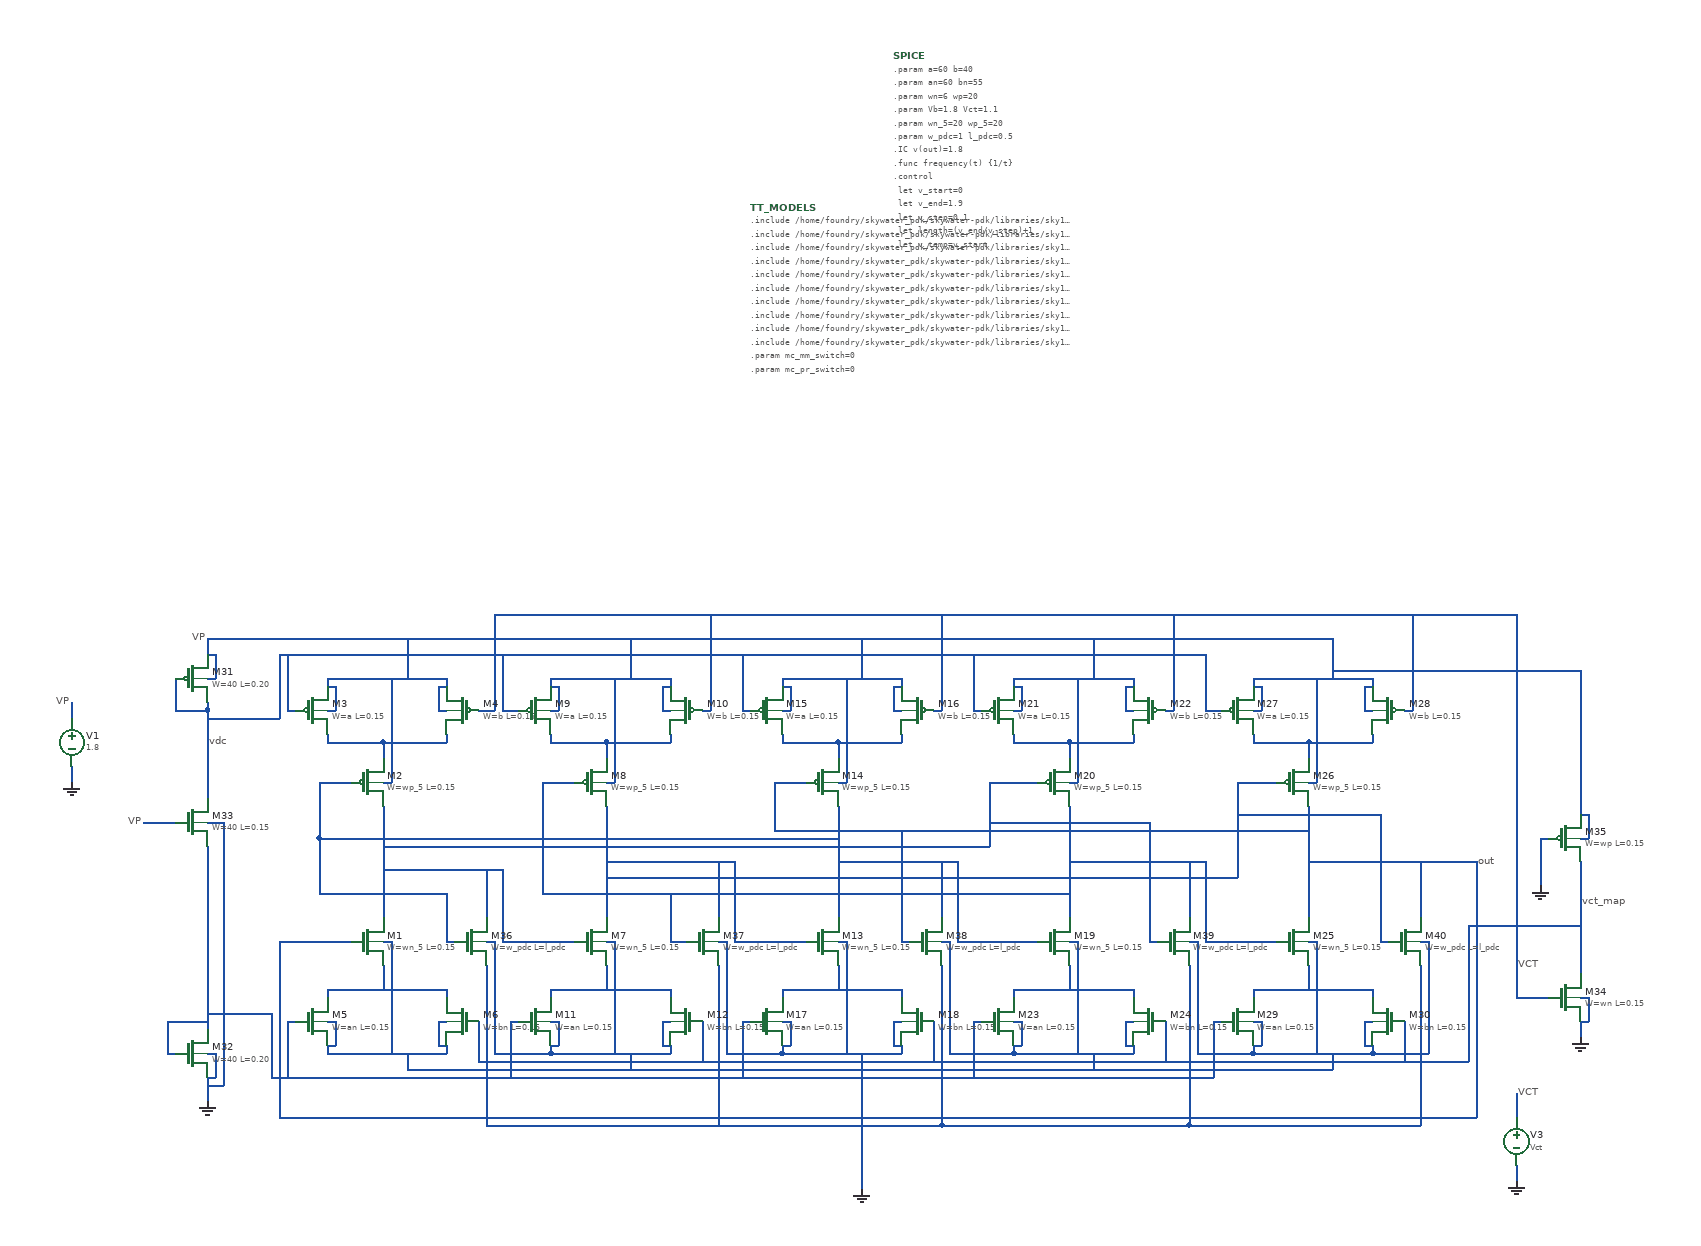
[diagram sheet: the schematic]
v {xschem version=3.0.0 file_version=1.2 }
G {}
K {}
V {}
S {}
E {}
N 50 -260 50 -120 { lab=#net1}
N 50 -290 60 -290 { lab=VP}
N 60 -320 60 -290 { lab=VP}
N 50 -90 60 -90 { lab=GND}
N 60 -90 60 -60 { lab=GND}
N 50 -340 50 -320 { lab=#net2}
N -20 -350 -20 -340 { lab=#net2}
N -20 -340 50 -340 { lab=#net2}
N 130 -350 130 -340 { lab=#net2}
N 50 -340 130 -340 { lab=#net2}
N -20 -380 -10 -380 { lab=VP}
N -10 -410 -10 -380 { lab=VP}
N -20 -410 -10 -410 { lab=VP}
N 120 -380 130 -380 { lab=VP}
N 120 -410 120 -380 { lab=VP}
N 120 -410 130 -410 { lab=VP}
N -20 -420 -20 -410 { lab=VP}
N -20 -420 130 -420 { lab=VP}
N 130 -420 130 -410 { lab=VP}
N -20 -30 -20 -20 { lab=#net3}
N -20 -30 130 -30 { lab=#net3}
N 130 -30 130 -20 { lab=#net3}
N -20 10 -10 10 { lab=GND}
N -10 10 -10 40 { lab=GND}
N -20 40 -10 40 { lab=GND}
N 120 10 130 10 { lab=GND}
N 120 10 120 40 { lab=GND}
N 120 40 130 40 { lab=GND}
N -20 40 -20 50 { lab=GND}
N -20 50 130 50 { lab=GND}
N 130 40 130 50 { lab=GND}
N 50 -60 50 -30 { lab=#net3}
N 330 -260 330 -120 { lab=#net4}
N 330 -290 340 -290 { lab=VP}
N 340 -320 340 -290 { lab=VP}
N 330 -90 340 -90 { lab=GND}
N 340 -90 340 -60 { lab=GND}
N 330 -340 330 -320 { lab=#net5}
N 260 -350 260 -340 { lab=#net5}
N 260 -340 330 -340 { lab=#net5}
N 410 -350 410 -340 { lab=#net5}
N 330 -340 410 -340 { lab=#net5}
N 260 -380 270 -380 { lab=VP}
N 270 -410 270 -380 { lab=VP}
N 260 -410 270 -410 { lab=VP}
N 400 -380 410 -380 { lab=VP}
N 400 -410 400 -380 { lab=VP}
N 400 -410 410 -410 { lab=VP}
N 260 -420 260 -410 { lab=VP}
N 260 -420 410 -420 { lab=VP}
N 410 -420 410 -410 { lab=VP}
N 260 -30 260 -20 { lab=#net6}
N 260 -30 410 -30 { lab=#net6}
N 410 -30 410 -20 { lab=#net6}
N 260 10 270 10 { lab=GND}
N 270 10 270 40 { lab=GND}
N 260 40 270 40 { lab=GND}
N 400 10 410 10 { lab=GND}
N 400 10 400 40 { lab=GND}
N 400 40 410 40 { lab=GND}
N 260 40 260 50 { lab=GND}
N 260 50 410 50 { lab=GND}
N 410 40 410 50 { lab=GND}
N 330 -60 330 -30 { lab=#net6}
N 620 -260 620 -120 { lab=#net7}
N 620 -290 630 -290 { lab=VP}
N 630 -320 630 -290 { lab=VP}
N 620 -90 630 -90 { lab=GND}
N 630 -90 630 -60 { lab=GND}
N 620 -340 620 -320 { lab=#net8}
N 550 -350 550 -340 { lab=#net8}
N 550 -340 620 -340 { lab=#net8}
N 700 -350 700 -340 { lab=#net8}
N 620 -340 700 -340 { lab=#net8}
N 550 -380 560 -380 { lab=VP}
N 560 -410 560 -380 { lab=VP}
N 550 -410 560 -410 { lab=VP}
N 690 -380 700 -380 { lab=VP}
N 690 -410 690 -380 { lab=VP}
N 690 -410 700 -410 { lab=VP}
N 550 -420 550 -410 { lab=VP}
N 550 -420 700 -420 { lab=VP}
N 700 -420 700 -410 { lab=VP}
N 550 -30 550 -20 { lab=#net9}
N 550 -30 700 -30 { lab=#net9}
N 700 -30 700 -20 { lab=#net9}
N 550 10 560 10 { lab=GND}
N 560 10 560 40 { lab=GND}
N 550 40 560 40 { lab=GND}
N 690 10 700 10 { lab=GND}
N 690 10 690 40 { lab=GND}
N 690 40 700 40 { lab=GND}
N 550 40 550 50 { lab=GND}
N 550 50 700 50 { lab=GND}
N 700 40 700 50 { lab=GND}
N 620 -60 620 -30 { lab=#net9}
N 910 -260 910 -120 { lab=#net10}
N 910 -290 920 -290 { lab=VP}
N 920 -320 920 -290 { lab=VP}
N 910 -90 920 -90 { lab=GND}
N 920 -90 920 -60 { lab=GND}
N 910 -340 910 -320 { lab=#net11}
N 840 -350 840 -340 { lab=#net11}
N 840 -340 910 -340 { lab=#net11}
N 990 -350 990 -340 { lab=#net11}
N 910 -340 990 -340 { lab=#net11}
N 840 -380 850 -380 { lab=VP}
N 850 -410 850 -380 { lab=VP}
N 840 -410 850 -410 { lab=VP}
N 980 -380 990 -380 { lab=VP}
N 980 -410 980 -380 { lab=VP}
N 980 -410 990 -410 { lab=VP}
N 840 -420 840 -410 { lab=VP}
N 840 -420 990 -420 { lab=VP}
N 990 -420 990 -410 { lab=VP}
N 840 -30 840 -20 { lab=#net12}
N 840 -30 990 -30 { lab=#net12}
N 990 -30 990 -20 { lab=#net12}
N 840 10 850 10 { lab=GND}
N 850 10 850 40 { lab=GND}
N 840 40 850 40 { lab=GND}
N 980 10 990 10 { lab=GND}
N 980 10 980 40 { lab=GND}
N 980 40 990 40 { lab=GND}
N 840 40 840 50 { lab=GND}
N 840 50 990 50 { lab=GND}
N 990 40 990 50 { lab=GND}
N 910 -60 910 -30 { lab=#net12}
N 1210 -260 1210 -120 { lab=out}
N 1210 -290 1220 -290 { lab=VP}
N 1220 -320 1220 -290 { lab=VP}
N 1210 -90 1220 -90 { lab=GND}
N 1220 -90 1220 -60 { lab=GND}
N 1210 -340 1210 -320 { lab=#net13}
N 1140 -350 1140 -340 { lab=#net13}
N 1140 -340 1210 -340 { lab=#net13}
N 1290 -350 1290 -340 { lab=#net13}
N 1210 -340 1290 -340 { lab=#net13}
N 1140 -380 1150 -380 { lab=VP}
N 1150 -410 1150 -380 { lab=VP}
N 1140 -410 1150 -410 { lab=VP}
N 1280 -380 1290 -380 { lab=VP}
N 1280 -410 1280 -380 { lab=VP}
N 1280 -410 1290 -410 { lab=VP}
N 1140 -420 1140 -410 { lab=VP}
N 1140 -420 1290 -420 { lab=VP}
N 1290 -420 1290 -410 { lab=VP}
N 1140 -30 1140 -20 { lab=#net14}
N 1140 -30 1290 -30 { lab=#net14}
N 1290 -30 1290 -20 { lab=#net14}
N 1140 10 1150 10 { lab=GND}
N 1150 10 1150 40 { lab=GND}
N 1140 40 1150 40 { lab=GND}
N 1280 10 1290 10 { lab=GND}
N 1280 10 1280 40 { lab=GND}
N 1280 40 1290 40 { lab=GND}
N 1140 40 1140 50 { lab=GND}
N 1140 50 1290 50 { lab=GND}
N 1290 40 1290 50 { lab=GND}
N 1210 -60 1210 -30 { lab=#net14}
N 60 -420 60 -320 { lab=VP}
N 340 -420 340 -320 { lab=VP}
N 630 -420 630 -320 { lab=VP}
N 920 -420 920 -320 { lab=VP}
N 1220 -420 1220 -320 { lab=VP}
N 60 -60 60 50 { lab=GND}
N 340 -60 340 50 { lab=GND}
N 630 -60 630 50 { lab=GND}
N 920 -60 920 50 { lab=GND}
N 1220 -60 1220 50 { lab=GND}
N 200 -90 290 -90 { lab=#net1}
N 200 -180 200 -90 { lab=#net1}
N 50 -180 200 -180 { lab=#net1}
N 490 -90 580 -90 { lab=#net4}
N 490 -190 490 -90 { lab=#net4}
N 330 -190 490 -190 { lab=#net4}
N 770 -90 870 -90 { lab=#net7}
N 770 -190 770 -90 { lab=#net7}
N 620 -190 770 -190 { lab=#net7}
N 910 -190 1070 -190 { lab=#net10}
N 1080 -190 1080 -90 { lab=#net10}
N -80 -90 -80 130 { lab=out}
N 1420 -190 1420 130 { lab=out}
N -340 -310 -340 -290 { lab=GND}
N -170 -470 1240 -470 { lab=VP}
N 1240 -460 1240 -420 { lab=VP}
N 80 -460 80 -420 { lab=VP}
N 360 -460 360 -420 { lab=VP}
N 650 -460 650 -420 { lab=VP}
N 940 -460 940 -420 { lab=VP}
N 80 50 80 70 { lab=GND}
N 80 70 1240 70 { lab=GND}
N 1240 50 1240 70 { lab=GND}
N 360 50 360 70 { lab=GND}
N 650 50 650 70 { lab=GND}
N 940 50 940 70 { lab=GND}
N 650 70 650 90 { lab=GND}
N 810 -290 870 -290 { lab=#net1}
N 810 -290 810 -210 { lab=#net1}
N 50 -210 810 -210 { lab=#net1}
N 1120 -290 1170 -290 { lab=#net4}
N 1120 -290 1120 -170 { lab=#net4}
N 330 -170 1120 -170 { lab=#net4}
N -30 -290 10 -290 { lab=#net7}
N -30 -290 -30 -220 { lab=#net7}
N -30 -220 620 -220 { lab=#net7}
N 250 -290 290 -290 { lab=#net10}
N 250 -290 250 -150 { lab=#net10}
N 250 -150 910 -150 { lab=#net10}
N 540 -290 580 -290 { lab=out}
N 540 -290 540 -230 { lab=out}
N 540 -230 1210 -230 { lab=out}
N -80 -90 10 -90 { lab=out}
N -210 -420 -210 -380 { lab=vdc}
N -210 -380 -170 -380 { lab=vdc}
N -170 -390 -170 -380 { lab=vdc}
N -170 -420 -160 -420 { lab=VP}
N -160 -450 -160 -420 { lab=VP}
N -170 -450 -160 -450 { lab=VP}
N 80 -470 80 -460 { lab=VP}
N 360 -470 360 -460 { lab=VP}
N 650 -470 650 -460 { lab=VP}
N 940 -470 940 -460 { lab=VP}
N 1240 -470 1240 -460 { lab=VP}
N -170 -470 -170 -450 { lab=VP}
N -170 -210 -170 20 { lab=#net15}
N -170 -380 -170 -270 { lab=vdc}
N -220 50 -210 50 { lab=#net15}
N -220 10 -220 50 { lab=#net15}
N -220 10 -170 10 { lab=#net15}
N -170 0 -90 0 { lab=#net15}
N -90 0 -90 80 { lab=#net15}
N -90 80 1090 80 { lab=#net15}
N 1090 10 1090 80 { lab=#net15}
N 1090 10 1100 10 { lab=#net15}
N 790 10 800 10 { lab=#net15}
N 790 10 790 80 { lab=#net15}
N 500 10 510 10 { lab=#net15}
N 500 10 500 80 { lab=#net15}
N 210 10 220 10 { lab=#net15}
N 210 10 210 80 { lab=#net15}
N -70 10 -60 10 { lab=#net15}
N -70 10 -70 80 { lab=#net15}
N -170 50 -160 50 { lab=GND}
N -160 50 -160 80 { lab=GND}
N -170 80 -160 80 { lab=GND}
N -170 80 -170 110 { lab=GND}
N -170 -370 -80 -370 { lab=vdc}
N -80 -450 -80 -370 { lab=vdc}
N -80 -450 1080 -450 { lab=vdc}
N 1080 -450 1080 -380 { lab=vdc}
N 1080 -380 1100 -380 { lab=vdc}
N 790 -380 800 -380 { lab=vdc}
N 790 -450 790 -380 { lab=vdc}
N 1470 190 1470 210 { lab=GND}
N 1470 -20 1510 -20 { lab=vct}
N 1550 -20 1560 -20 { lab=GND}
N 1560 -20 1560 10 { lab=GND}
N 1550 10 1560 10 { lab=GND}
N 1550 10 1550 30 { lab=GND}
N 1550 -220 1560 -220 { lab=VP}
N 1560 -250 1560 -220 { lab=VP}
N 1550 -250 1560 -250 { lab=VP}
N 1550 -430 1550 -250 { lab=VP}
N 1240 -430 1550 -430 { lab=VP}
N 1550 -190 1550 -50 { lab=vct_map}
N 1470 -500 1470 -20 { lab=vct}
N 190 -500 1470 -500 { lab=vct}
N 190 -500 190 -380 { lab=vct}
N 170 -380 190 -380 { lab=vct}
N -70 -380 -60 -380 { lab=vdc}
N -70 -450 -70 -380 { lab=vdc}
N 200 -380 220 -380 { lab=vdc}
N 200 -450 200 -380 { lab=vdc}
N 500 -380 510 -380 { lab=vdc}
N 500 -450 500 -380 { lab=vdc}
N 450 -380 460 -380 { lab=vct}
N 460 -500 460 -380 { lab=vct}
N 740 -380 750 -380 { lab=vct}
N 750 -500 750 -380 { lab=vct}
N 1030 -380 1040 -380 { lab=vct}
N 1040 -500 1040 -380 { lab=vct}
N 1500 -220 1510 -220 { lab=GND}
N 1500 -220 1500 -180 { lab=GND}
N 1450 -110 1550 -110 { lab=vct_map}
N 1410 -110 1450 -110 { lab=vct_map}
N 1410 -110 1410 60 { lab=vct_map}
N 170 60 1410 60 { lab=vct_map}
N 170 10 170 60 { lab=vct_map}
N 450 10 450 60 { lab=vct_map}
N 740 10 740 60 { lab=vct_map}
N 1030 10 1030 60 { lab=vct_map}
N 1330 10 1330 60 { lab=vct_map}
N 1330 -380 1340 -380 { lab=vct}
N 1340 -500 1340 -380 { lab=vct}
N 1210 -190 1360 -190 { lab=out}
N -80 130 1360 130 { lab=out}
N 1500 -180 1500 -160 { lab=GND}
N -170 -240 -150 -240 { lab=GND}
N -150 -240 -150 90 { lab=GND}
N -170 90 -150 90 { lab=GND}
N -250 -240 -210 -240 { lab=VP}
N 180 -60 180 140 { lab=GND}
N 470 -60 470 140 { lab=GND}
N 750 -60 750 140 { lab=GND}
N 1060 -60 1060 140 { lab=GND}
N 1350 -60 1350 140 { lab=GND}
N 650 90 650 220 { lab=GND}
N 180 -180 180 -120 { lab=#net1}
N 470 -190 470 -120 { lab=#net4}
N 750 -190 750 -120 { lab=#net7}
N 1060 -190 1060 -120 { lab=#net10}
N 1350 -190 1350 -120 { lab=out}
N 130 -90 140 -90 { lab=#net7}
N 130 -150 130 -90 { lab=#net7}
N -30 -150 130 -150 { lab=#net7}
N -30 -220 -30 -150 { lab=#net7}
N 410 -90 430 -90 { lab=#net10}
N 410 -150 410 -90 { lab=#net10}
N 700 -90 710 -90 { lab=out}
N 700 -230 700 -90 { lab=out}
N 1010 -90 1020 -90 { lab=#net1}
N 1010 -240 1010 -90 { lab=#net1}
N 810 -240 1010 -240 { lab=#net1}
N 1300 -90 1310 -90 { lab=#net4}
N 1300 -250 1300 -90 { lab=#net4}
N 1120 -250 1300 -250 { lab=#net4}
N 180 -90 190 -90 { lab=GND}
N 190 -90 190 50 { lab=GND}
N 190 50 260 50 { lab=GND}
N 470 -90 480 -90 { lab=GND}
N 480 -90 480 50 { lab=GND}
N 480 50 550 50 { lab=GND}
N 750 -90 760 -90 { lab=GND}
N 760 -90 760 50 { lab=GND}
N 760 50 840 50 { lab=GND}
N 1070 50 1140 50 { lab=GND}
N 1070 -190 1080 -190 { lab=#net10}
N 1080 -90 1170 -90 { lab=#net10}
N 1060 -90 1070 -90 { lab=GND}
N 1070 -90 1070 50 { lab=GND}
N 1360 130 1420 130 { lab=out}
N 1360 -190 1420 -190 { lab=out}
N 1350 -90 1360 -90 { lab=GND}
N 1360 -90 1360 50 { lab=GND}
N 1290 50 1360 50 { lab=GND}
N 180 140 650 140 { lab=GND}
N 650 140 750 140 { lab=GND}
N 750 140 1060 140 { lab=GND}
N 1060 140 1350 140 { lab=GND}
N -340 -390 -340 -370 { lab=VP}
N 1470 100 1470 130 { lab=VCT}
C {xschem_sky130/sky130_fd_pr/nfet_01v8.sym} 30 -90 0 0 {name=M1
L=0.15
W=wn_5
nf=4 
mult=1
ad="'int((nf+1)/2) * W/nf * 0.29'" 
pd="'2*int((nf+1)/2) * (W/nf + 0.29)'"
as="'int((nf+2)/2) * W/nf * 0.29'" 
ps="'2*int((nf+2)/2) * (W/nf + 0.29)'"
nrd="'0.29 / W'" nrs="'0.29 / W'"
sa=0 sb=0 sd=0
model=nfet_01v8
spiceprefix=X
}
C {xschem_sky130/sky130_fd_pr/pfet_01v8.sym} 30 -290 0 0 {name=M2
L=0.15
W=wp_5
nf=4
mult=1
ad="'int((nf+1)/2) * W/nf * 0.29'" 
pd="'2*int((nf+1)/2) * (W/nf + 0.29)'"
as="'int((nf+2)/2) * W/nf * 0.29'" 
ps="'2*int((nf+2)/2) * (W/nf + 0.29)'"
nrd="'0.29 / W'" nrs="'0.29 / W'"
sa=0 sb=0 sd=0
model=pfet_01v8
spiceprefix=X
}
C {xschem_sky130/sky130_fd_pr/pfet_01v8.sym} -40 -380 0 0 {name=M3
L=0.15
W=a
nf=12
mult=1
ad="'int((nf+1)/2) * W/nf * 0.29'" 
pd="'2*int((nf+1)/2) * (W/nf + 0.29)'"
as="'int((nf+2)/2) * W/nf * 0.29'" 
ps="'2*int((nf+2)/2) * (W/nf + 0.29)'"
nrd="'0.29 / W'" nrs="'0.29 / W'"
sa=0 sb=0 sd=0
model=pfet_01v8
spiceprefix=X
}
C {xschem_sky130/sky130_fd_pr/pfet_01v8.sym} 150 -380 0 1 {name=M4
L=0.15
W=b
nf=8
mult=1
ad="'int((nf+1)/2) * W/nf * 0.29'" 
pd="'2*int((nf+1)/2) * (W/nf + 0.29)'"
as="'int((nf+2)/2) * W/nf * 0.29'" 
ps="'2*int((nf+2)/2) * (W/nf + 0.29)'"
nrd="'0.29 / W'" nrs="'0.29 / W'"
sa=0 sb=0 sd=0
model=pfet_01v8
spiceprefix=X
}
C {xschem_sky130/sky130_fd_pr/nfet_01v8.sym} -40 10 0 0 {name=M5
L=0.15
W=an
nf=12 
mult=1
ad="'int((nf+1)/2) * W/nf * 0.29'" 
pd="'2*int((nf+1)/2) * (W/nf + 0.29)'"
as="'int((nf+2)/2) * W/nf * 0.29'" 
ps="'2*int((nf+2)/2) * (W/nf + 0.29)'"
nrd="'0.29 / W'" nrs="'0.29 / W'"
sa=0 sb=0 sd=0
model=nfet_01v8
spiceprefix=X
}
C {xschem_sky130/sky130_fd_pr/nfet_01v8.sym} 150 10 0 1 {name=M6
L=0.15
W=bn
nf=11 
mult=1
ad="'int((nf+1)/2) * W/nf * 0.29'" 
pd="'2*int((nf+1)/2) * (W/nf + 0.29)'"
as="'int((nf+2)/2) * W/nf * 0.29'" 
ps="'2*int((nf+2)/2) * (W/nf + 0.29)'"
nrd="'0.29 / W'" nrs="'0.29 / W'"
sa=0 sb=0 sd=0
model=nfet_01v8
spiceprefix=X
}
C {xschem_sky130/sky130_fd_pr/nfet_01v8.sym} 310 -90 0 0 {name=M7
L=0.15
W=wn_5
nf=4 
mult=1
ad="'int((nf+1)/2) * W/nf * 0.29'" 
pd="'2*int((nf+1)/2) * (W/nf + 0.29)'"
as="'int((nf+2)/2) * W/nf * 0.29'" 
ps="'2*int((nf+2)/2) * (W/nf + 0.29)'"
nrd="'0.29 / W'" nrs="'0.29 / W'"
sa=0 sb=0 sd=0
model=nfet_01v8
spiceprefix=X
}
C {xschem_sky130/sky130_fd_pr/pfet_01v8.sym} 310 -290 0 0 {name=M8
L=0.15
W=wp_5
nf=4
mult=1
ad="'int((nf+1)/2) * W/nf * 0.29'" 
pd="'2*int((nf+1)/2) * (W/nf + 0.29)'"
as="'int((nf+2)/2) * W/nf * 0.29'" 
ps="'2*int((nf+2)/2) * (W/nf + 0.29)'"
nrd="'0.29 / W'" nrs="'0.29 / W'"
sa=0 sb=0 sd=0
model=pfet_01v8
spiceprefix=X
}
C {xschem_sky130/sky130_fd_pr/pfet_01v8.sym} 240 -380 0 0 {name=M9
L=0.15
W=a
nf=12
mult=1
ad="'int((nf+1)/2) * W/nf * 0.29'" 
pd="'2*int((nf+1)/2) * (W/nf + 0.29)'"
as="'int((nf+2)/2) * W/nf * 0.29'" 
ps="'2*int((nf+2)/2) * (W/nf + 0.29)'"
nrd="'0.29 / W'" nrs="'0.29 / W'"
sa=0 sb=0 sd=0
model=pfet_01v8
spiceprefix=X
}
C {xschem_sky130/sky130_fd_pr/pfet_01v8.sym} 430 -380 0 1 {name=M10
L=0.15
W=b
nf=8
mult=1
ad="'int((nf+1)/2) * W/nf * 0.29'" 
pd="'2*int((nf+1)/2) * (W/nf + 0.29)'"
as="'int((nf+2)/2) * W/nf * 0.29'" 
ps="'2*int((nf+2)/2) * (W/nf + 0.29)'"
nrd="'0.29 / W'" nrs="'0.29 / W'"
sa=0 sb=0 sd=0
model=pfet_01v8
spiceprefix=X
}
C {xschem_sky130/sky130_fd_pr/nfet_01v8.sym} 240 10 0 0 {name=M11
L=0.15
W=an
nf=12 
mult=1
ad="'int((nf+1)/2) * W/nf * 0.29'" 
pd="'2*int((nf+1)/2) * (W/nf + 0.29)'"
as="'int((nf+2)/2) * W/nf * 0.29'" 
ps="'2*int((nf+2)/2) * (W/nf + 0.29)'"
nrd="'0.29 / W'" nrs="'0.29 / W'"
sa=0 sb=0 sd=0
model=nfet_01v8
spiceprefix=X
}
C {xschem_sky130/sky130_fd_pr/nfet_01v8.sym} 430 10 0 1 {name=M12
L=0.15
W=bn
nf=11 
mult=1
ad="'int((nf+1)/2) * W/nf * 0.29'" 
pd="'2*int((nf+1)/2) * (W/nf + 0.29)'"
as="'int((nf+2)/2) * W/nf * 0.29'" 
ps="'2*int((nf+2)/2) * (W/nf + 0.29)'"
nrd="'0.29 / W'" nrs="'0.29 / W'"
sa=0 sb=0 sd=0
model=nfet_01v8
spiceprefix=X
}
C {xschem_sky130/sky130_fd_pr/nfet_01v8.sym} 600 -90 0 0 {name=M13
L=0.15
W=wn_5
nf=4 
mult=1
ad="'int((nf+1)/2) * W/nf * 0.29'" 
pd="'2*int((nf+1)/2) * (W/nf + 0.29)'"
as="'int((nf+2)/2) * W/nf * 0.29'" 
ps="'2*int((nf+2)/2) * (W/nf + 0.29)'"
nrd="'0.29 / W'" nrs="'0.29 / W'"
sa=0 sb=0 sd=0
model=nfet_01v8
spiceprefix=X
}
C {xschem_sky130/sky130_fd_pr/pfet_01v8.sym} 600 -290 0 0 {name=M14
L=0.15
W=wp_5
nf=4
mult=1
ad="'int((nf+1)/2) * W/nf * 0.29'" 
pd="'2*int((nf+1)/2) * (W/nf + 0.29)'"
as="'int((nf+2)/2) * W/nf * 0.29'" 
ps="'2*int((nf+2)/2) * (W/nf + 0.29)'"
nrd="'0.29 / W'" nrs="'0.29 / W'"
sa=0 sb=0 sd=0
model=pfet_01v8
spiceprefix=X
}
C {xschem_sky130/sky130_fd_pr/pfet_01v8.sym} 530 -380 0 0 {name=M15
L=0.15
W=a
nf=12
mult=1
ad="'int((nf+1)/2) * W/nf * 0.29'" 
pd="'2*int((nf+1)/2) * (W/nf + 0.29)'"
as="'int((nf+2)/2) * W/nf * 0.29'" 
ps="'2*int((nf+2)/2) * (W/nf + 0.29)'"
nrd="'0.29 / W'" nrs="'0.29 / W'"
sa=0 sb=0 sd=0
model=pfet_01v8
spiceprefix=X
}
C {xschem_sky130/sky130_fd_pr/pfet_01v8.sym} 720 -380 0 1 {name=M16
L=0.15
W=b
nf=8
mult=1
ad="'int((nf+1)/2) * W/nf * 0.29'" 
pd="'2*int((nf+1)/2) * (W/nf + 0.29)'"
as="'int((nf+2)/2) * W/nf * 0.29'" 
ps="'2*int((nf+2)/2) * (W/nf + 0.29)'"
nrd="'0.29 / W'" nrs="'0.29 / W'"
sa=0 sb=0 sd=0
model=pfet_01v8
spiceprefix=X
}
C {xschem_sky130/sky130_fd_pr/nfet_01v8.sym} 530 10 0 0 {name=M17
L=0.15
W=an
nf=12 
mult=1
ad="'int((nf+1)/2) * W/nf * 0.29'" 
pd="'2*int((nf+1)/2) * (W/nf + 0.29)'"
as="'int((nf+2)/2) * W/nf * 0.29'" 
ps="'2*int((nf+2)/2) * (W/nf + 0.29)'"
nrd="'0.29 / W'" nrs="'0.29 / W'"
sa=0 sb=0 sd=0
model=nfet_01v8
spiceprefix=X
}
C {xschem_sky130/sky130_fd_pr/nfet_01v8.sym} 720 10 0 1 {name=M18
L=0.15
W=bn
nf=11 
mult=1
ad="'int((nf+1)/2) * W/nf * 0.29'" 
pd="'2*int((nf+1)/2) * (W/nf + 0.29)'"
as="'int((nf+2)/2) * W/nf * 0.29'" 
ps="'2*int((nf+2)/2) * (W/nf + 0.29)'"
nrd="'0.29 / W'" nrs="'0.29 / W'"
sa=0 sb=0 sd=0
model=nfet_01v8
spiceprefix=X
}
C {xschem_sky130/sky130_fd_pr/nfet_01v8.sym} 890 -90 0 0 {name=M19
L=0.15
W=wn_5
nf=4 
mult=1
ad="'int((nf+1)/2) * W/nf * 0.29'" 
pd="'2*int((nf+1)/2) * (W/nf + 0.29)'"
as="'int((nf+2)/2) * W/nf * 0.29'" 
ps="'2*int((nf+2)/2) * (W/nf + 0.29)'"
nrd="'0.29 / W'" nrs="'0.29 / W'"
sa=0 sb=0 sd=0
model=nfet_01v8
spiceprefix=X
}
C {xschem_sky130/sky130_fd_pr/pfet_01v8.sym} 890 -290 0 0 {name=M20
L=0.15
W=wp_5
nf=4
mult=1
ad="'int((nf+1)/2) * W/nf * 0.29'" 
pd="'2*int((nf+1)/2) * (W/nf + 0.29)'"
as="'int((nf+2)/2) * W/nf * 0.29'" 
ps="'2*int((nf+2)/2) * (W/nf + 0.29)'"
nrd="'0.29 / W'" nrs="'0.29 / W'"
sa=0 sb=0 sd=0
model=pfet_01v8
spiceprefix=X
}
C {xschem_sky130/sky130_fd_pr/pfet_01v8.sym} 820 -380 0 0 {name=M21
L=0.15
W=a
nf=12
mult=1
ad="'int((nf+1)/2) * W/nf * 0.29'" 
pd="'2*int((nf+1)/2) * (W/nf + 0.29)'"
as="'int((nf+2)/2) * W/nf * 0.29'" 
ps="'2*int((nf+2)/2) * (W/nf + 0.29)'"
nrd="'0.29 / W'" nrs="'0.29 / W'"
sa=0 sb=0 sd=0
model=pfet_01v8
spiceprefix=X
}
C {xschem_sky130/sky130_fd_pr/pfet_01v8.sym} 1010 -380 0 1 {name=M22
L=0.15
W=b
nf=8
mult=1
ad="'int((nf+1)/2) * W/nf * 0.29'" 
pd="'2*int((nf+1)/2) * (W/nf + 0.29)'"
as="'int((nf+2)/2) * W/nf * 0.29'" 
ps="'2*int((nf+2)/2) * (W/nf + 0.29)'"
nrd="'0.29 / W'" nrs="'0.29 / W'"
sa=0 sb=0 sd=0
model=pfet_01v8
spiceprefix=X
}
C {xschem_sky130/sky130_fd_pr/nfet_01v8.sym} 820 10 0 0 {name=M23
L=0.15
W=an
nf=12 
mult=1
ad="'int((nf+1)/2) * W/nf * 0.29'" 
pd="'2*int((nf+1)/2) * (W/nf + 0.29)'"
as="'int((nf+2)/2) * W/nf * 0.29'" 
ps="'2*int((nf+2)/2) * (W/nf + 0.29)'"
nrd="'0.29 / W'" nrs="'0.29 / W'"
sa=0 sb=0 sd=0
model=nfet_01v8
spiceprefix=X
}
C {xschem_sky130/sky130_fd_pr/nfet_01v8.sym} 1010 10 0 1 {name=M24
L=0.15
W=bn
nf=11 
mult=1
ad="'int((nf+1)/2) * W/nf * 0.29'" 
pd="'2*int((nf+1)/2) * (W/nf + 0.29)'"
as="'int((nf+2)/2) * W/nf * 0.29'" 
ps="'2*int((nf+2)/2) * (W/nf + 0.29)'"
nrd="'0.29 / W'" nrs="'0.29 / W'"
sa=0 sb=0 sd=0
model=nfet_01v8
spiceprefix=X
}
C {xschem_sky130/sky130_fd_pr/nfet_01v8.sym} 1190 -90 0 0 {name=M25
L=0.15
W=wn_5
nf=4 
mult=1
ad="'int((nf+1)/2) * W/nf * 0.29'" 
pd="'2*int((nf+1)/2) * (W/nf + 0.29)'"
as="'int((nf+2)/2) * W/nf * 0.29'" 
ps="'2*int((nf+2)/2) * (W/nf + 0.29)'"
nrd="'0.29 / W'" nrs="'0.29 / W'"
sa=0 sb=0 sd=0
model=nfet_01v8
spiceprefix=X
}
C {xschem_sky130/sky130_fd_pr/pfet_01v8.sym} 1190 -290 0 0 {name=M26
L=0.15
W=wp_5
nf=4
mult=1
ad="'int((nf+1)/2) * W/nf * 0.29'" 
pd="'2*int((nf+1)/2) * (W/nf + 0.29)'"
as="'int((nf+2)/2) * W/nf * 0.29'" 
ps="'2*int((nf+2)/2) * (W/nf + 0.29)'"
nrd="'0.29 / W'" nrs="'0.29 / W'"
sa=0 sb=0 sd=0
model=pfet_01v8
spiceprefix=X
}
C {xschem_sky130/sky130_fd_pr/pfet_01v8.sym} 1120 -380 0 0 {name=M27
L=0.15
W=a
nf=12
mult=1
ad="'int((nf+1)/2) * W/nf * 0.29'" 
pd="'2*int((nf+1)/2) * (W/nf + 0.29)'"
as="'int((nf+2)/2) * W/nf * 0.29'" 
ps="'2*int((nf+2)/2) * (W/nf + 0.29)'"
nrd="'0.29 / W'" nrs="'0.29 / W'"
sa=0 sb=0 sd=0
model=pfet_01v8
spiceprefix=X
}
C {xschem_sky130/sky130_fd_pr/pfet_01v8.sym} 1310 -380 0 1 {name=M28
L=0.15
W=b
nf=8
mult=1
ad="'int((nf+1)/2) * W/nf * 0.29'" 
pd="'2*int((nf+1)/2) * (W/nf + 0.29)'"
as="'int((nf+2)/2) * W/nf * 0.29'" 
ps="'2*int((nf+2)/2) * (W/nf + 0.29)'"
nrd="'0.29 / W'" nrs="'0.29 / W'"
sa=0 sb=0 sd=0
model=pfet_01v8
spiceprefix=X
}
C {xschem_sky130/sky130_fd_pr/nfet_01v8.sym} 1120 10 0 0 {name=M29
L=0.15
W=an
nf=12 
mult=1
ad="'int((nf+1)/2) * W/nf * 0.29'" 
pd="'2*int((nf+1)/2) * (W/nf + 0.29)'"
as="'int((nf+2)/2) * W/nf * 0.29'" 
ps="'2*int((nf+2)/2) * (W/nf + 0.29)'"
nrd="'0.29 / W'" nrs="'0.29 / W'"
sa=0 sb=0 sd=0
model=nfet_01v8
spiceprefix=X
}
C {xschem_sky130/sky130_fd_pr/nfet_01v8.sym} 1310 10 0 1 {name=M30
L=0.15
W=bn
nf=11 
mult=1
ad="'int((nf+1)/2) * W/nf * 0.29'" 
pd="'2*int((nf+1)/2) * (W/nf + 0.29)'"
as="'int((nf+2)/2) * W/nf * 0.29'" 
ps="'2*int((nf+2)/2) * (W/nf + 0.29)'"
nrd="'0.29 / W'" nrs="'0.29 / W'"
sa=0 sb=0 sd=0
model=nfet_01v8
spiceprefix=X
}
C {vsource.sym} -340 -340 0 0 {name=V1 value=1.8}
C {gnd.sym} -340 -290 0 0 {name=l1 lab=GND}
C {xschem_sky130/sky130_fd_pr/pfet_01v8.sym} -190 -420 0 0 {name=M31
L=0.20
W=40
nf=8
mult=1
ad="'int((nf+1)/2) * W/nf * 0.29'" 
pd="'2*int((nf+1)/2) * (W/nf + 0.29)'"
as="'int((nf+2)/2) * W/nf * 0.29'" 
ps="'2*int((nf+2)/2) * (W/nf + 0.29)'"
nrd="'0.29 / W'" nrs="'0.29 / W'"
sa=0 sb=0 sd=0
model=pfet_01v8
spiceprefix=X
}
C {xschem_sky130/sky130_fd_pr/nfet_01v8.sym} -190 50 0 0 {name=M32
L=0.20
W=40
nf=8
mult=1
ad="'int((nf+1)/2) * W/nf * 0.29'" 
pd="'2*int((nf+1)/2) * (W/nf + 0.29)'"
as="'int((nf+2)/2) * W/nf * 0.29'" 
ps="'2*int((nf+2)/2) * (W/nf + 0.29)'"
nrd="'0.29 / W'" nrs="'0.29 / W'"
sa=0 sb=0 sd=0
model=nfet_01v8
spiceprefix=X
}
C {gnd.sym} -170 110 0 0 {name=l4 lab=GND}
C {xschem_sky130/sky130_fd_pr/nfet_01v8.sym} 1530 -20 0 0 {name=M34
L=0.15
W=wn
nf=1 
mult=1
ad="'int((nf+1)/2) * W/nf * 0.29'" 
pd="'2*int((nf+1)/2) * (W/nf + 0.29)'"
as="'int((nf+2)/2) * W/nf * 0.29'" 
ps="'2*int((nf+2)/2) * (W/nf + 0.29)'"
nrd="'0.29 / W'" nrs="'0.29 / W'"
sa=0 sb=0 sd=0
model=nfet_01v8
spiceprefix=X
}
C {vsource.sym} 1470 160 0 0 {name=V3 value=Vct}
C {gnd.sym} 1470 210 0 0 {name=l5 lab=GND}
C {xschem_sky130/sky130_fd_pr/pfet_01v8.sym} 1530 -220 0 0 {name=M35
L=0.15
W=wp
nf=4
mult=1
ad="'int((nf+1)/2) * W/nf * 0.29'" 
pd="'2*int((nf+1)/2) * (W/nf + 0.29)'"
as="'int((nf+2)/2) * W/nf * 0.29'" 
ps="'2*int((nf+2)/2) * (W/nf + 0.29)'"
nrd="'0.29 / W'" nrs="'0.29 / W'"
sa=0 sb=0 sd=0
model=pfet_01v8
spiceprefix=X
}
C {gnd.sym} 1550 30 0 0 {name=l6 lab=GND}
C {code.sym} 510 -1010 0 0 {name=TT_MODELS
only_toplevel=true
format="tcleval( @value )"
value=".include /home/foundry/skywater_pdk/skywater-pdk/libraries/sky130_fd_pr_ngspice/latest/models/corners/tt/nonfet.spice
.include /home/foundry/skywater_pdk/skywater-pdk/libraries/sky130_fd_pr_ngspice/latest/models/all.spice 
.include /home/foundry/skywater_pdk/skywater-pdk/libraries/sky130_fd_pr/latest/cells/pfet_01v8_lvt/sky130_fd_pr__pfet_01v8_lvt__tt.corner.spice
.include /home/foundry/skywater_pdk/skywater-pdk/libraries/sky130_fd_pr/latest/cells/nfet_01v8_lvt/sky130_fd_pr__nfet_01v8_lvt__tt.corner.spice
.include /home/foundry/skywater_pdk/skywater-pdk/libraries/sky130_fd_pr/latest/cells/pfet_01v8_lvt/sky130_fd_pr__pfet_01v8_lvt__mismatch.corner.spice
.include /home/foundry/skywater_pdk/skywater-pdk/libraries/sky130_fd_pr/latest/cells/nfet_01v8_lvt/sky130_fd_pr__nfet_01v8_lvt__mismatch.corner.spice
.include /home/foundry/skywater_pdk/skywater-pdk/libraries/sky130_fd_pr/latest/cells/pfet_01v8/sky130_fd_pr__pfet_01v8__tt.corner.spice
.include /home/foundry/skywater_pdk/skywater-pdk/libraries/sky130_fd_pr/latest/cells/nfet_01v8/sky130_fd_pr__nfet_01v8__tt.corner.spice
.include /home/foundry/skywater_pdk/skywater-pdk/libraries/sky130_fd_pr/latest/cells/pfet_01v8/sky130_fd_pr__pfet_01v8__mismatch.corner.spice
.include /home/foundry/skywater_pdk/skywater-pdk/libraries/sky130_fd_pr/latest/cells/nfet_01v8/sky130_fd_pr__nfet_01v8__mismatch.corner.spice
.param mc_mm_switch=0
.param mc_pr_switch=0
"
spice_ignore=false}
C {code_shown.sym} 690 -1200 0 0 {name=SPICE 
only_toplevel=false 
value=".param a=60 b=40
.param an=60 bn=55
.param wn=6 wp=20
.param Vb=1.8 Vct=1.1
.param wn_5=20 wp_5=20
.param w_pdc=1 l_pdc=0.5
.IC v(out)=1.8
.func frequency(t) \{1/t\}
.control
      let v_start=0
      let v_end=1.9
      let v_step=0.1
      let length=(v_end/v_step)+1
      let v_temp=v_start
      let freq=unitvec(length)
      let v_control=unitvec(length)
      let v_map=unitvec(length)
      let count=0
      while v_temp le v_end
            alter V3 v_temp
            let v_control[count]=v_temp
            tran 1000p 20n UIC
	    meas tran yeval FIND v(vct_map) AT=10n
	    let v_map[count]=yeval
            meas tran tdiff TRIG v(out) VAL=0.9 RISE=58 TARG v(out) VAL=0.9 RISE=59
            let freq[count]=frequency(tdiff)
            let v_temp=v_temp+v_step
            let count=count+1
            echo after while loop "%loop"
      end
      write 5_Stage_VCRO_CSA_PDC.raw
      plot freq vs v_control
      plot v_map vs v_control
.endc
.save all"}
C {lab_pin.sym} 1420 -190 0 1 {name=l7 sig_type=std_logic lab=out}
C {lab_pin.sym} 1550 -140 0 1 {name=l8 sig_type=std_logic lab=vct_map}
C {lab_pin.sym} 1470 -60 0 1 {name=l9 sig_type=std_logic lab=VCT}
C {gnd.sym} 1500 -160 0 0 {name=l10 lab=GND}
C {xschem_sky130/sky130_fd_pr/nfet_01v8.sym} -190 -240 0 0 {name=M33
L=0.15
W=40
nf=8
mult=1
ad="'int((nf+1)/2) * W/nf * 0.29'" 
pd="'2*int((nf+1)/2) * (W/nf + 0.29)'"
as="'int((nf+2)/2) * W/nf * 0.29'" 
ps="'2*int((nf+2)/2) * (W/nf + 0.29)'"
nrd="'0.29 / W'" nrs="'0.29 / W'"
sa=0 sb=0 sd=0
model=nfet_01v8
spiceprefix=X
}
C {lab_pin.sym} -170 -340 0 1 {name=l11 sig_type=std_logic lab=vdc}
C {xschem_sky130/sky130_fd_pr/nfet_01v8.sym} 160 -90 0 0 {name=M36
L=l_pdc
W=w_pdc
nf=1
mult=1
ad="'int((nf+1)/2) * W/nf * 0.29'" 
pd="'2*int((nf+1)/2) * (W/nf + 0.29)'"
as="'int((nf+2)/2) * W/nf * 0.29'" 
ps="'2*int((nf+2)/2) * (W/nf + 0.29)'"
nrd="'0.29 / W'" nrs="'0.29 / W'"
sa=0 sb=0 sd=0
model=nfet_01v8
spiceprefix=X
}
C {xschem_sky130/sky130_fd_pr/nfet_01v8.sym} 450 -90 0 0 {name=M37
L=l_pdc
W=w_pdc
nf=1 
mult=1
ad="'int((nf+1)/2) * W/nf * 0.29'" 
pd="'2*int((nf+1)/2) * (W/nf + 0.29)'"
as="'int((nf+2)/2) * W/nf * 0.29'" 
ps="'2*int((nf+2)/2) * (W/nf + 0.29)'"
nrd="'0.29 / W'" nrs="'0.29 / W'"
sa=0 sb=0 sd=0
model=nfet_01v8
spiceprefix=X
}
C {xschem_sky130/sky130_fd_pr/nfet_01v8.sym} 730 -90 0 0 {name=M38
L=l_pdc
W=w_pdc
nf=1 
mult=1
ad="'int((nf+1)/2) * W/nf * 0.29'" 
pd="'2*int((nf+1)/2) * (W/nf + 0.29)'"
as="'int((nf+2)/2) * W/nf * 0.29'" 
ps="'2*int((nf+2)/2) * (W/nf + 0.29)'"
nrd="'0.29 / W'" nrs="'0.29 / W'"
sa=0 sb=0 sd=0
model=nfet_01v8
spiceprefix=X
}
C {xschem_sky130/sky130_fd_pr/nfet_01v8.sym} 1040 -90 0 0 {name=M39
L=l_pdc
W=w_pdc
nf=1 
mult=1
ad="'int((nf+1)/2) * W/nf * 0.29'" 
pd="'2*int((nf+1)/2) * (W/nf + 0.29)'"
as="'int((nf+2)/2) * W/nf * 0.29'" 
ps="'2*int((nf+2)/2) * (W/nf + 0.29)'"
nrd="'0.29 / W'" nrs="'0.29 / W'"
sa=0 sb=0 sd=0
model=nfet_01v8
spiceprefix=X
}
C {xschem_sky130/sky130_fd_pr/nfet_01v8.sym} 1330 -90 0 0 {name=M40
L=l_pdc
W=w_pdc
nf=1 
mult=1
ad="'int((nf+1)/2) * W/nf * 0.29'" 
pd="'2*int((nf+1)/2) * (W/nf + 0.29)'"
as="'int((nf+2)/2) * W/nf * 0.29'" 
ps="'2*int((nf+2)/2) * (W/nf + 0.29)'"
nrd="'0.29 / W'" nrs="'0.29 / W'"
sa=0 sb=0 sd=0
model=nfet_01v8
spiceprefix=X
}
C {gnd.sym} 650 220 0 0 {name=l2 lab=GND}
C {lab_pin.sym} -340 -390 0 0 {name=l12 sig_type=std_logic lab=VP}
C {lab_pin.sym} -170 -470 0 0 {name=l13 sig_type=std_logic lab=VP}
C {lab_pin.sym} -250 -240 0 0 {name=l3 sig_type=std_logic lab=VP}
C {lab_pin.sym} 1470 100 0 1 {name=l14 sig_type=std_logic lab=VCT}
